VERSION 5.8 ;
BUSBITCHARS "[]" ;
DIVIDERCHAR "/" ;
UNITS
    DATABASE MICRONS 1000 ;
END UNITS

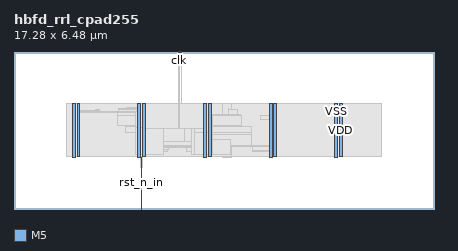
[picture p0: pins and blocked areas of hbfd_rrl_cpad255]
MACRO hbfd_rrl_cpad255
  FOREIGN hbfd_rrl_cpad255 0 0 ;
  CLASS BLOCK ;
  SIZE 17.28 BY 6.48 ;
  PIN clk
    DIRECTION INPUT ;
    USE SIGNAL ;
    PORT
      LAYER M5 ;
        RECT  6.768 6.396 6.792 6.48 ;
    END
  END clk
  PIN rst_n
    DIRECTION OUTPUT ;
    USE SIGNAL ;
    PORT
      LAYER M5 ;
        RECT  6.864 6.396 6.888 6.48 ;
    END
  END rst_n
  PIN rst_n_in
    DIRECTION INPUT ;
    USE SIGNAL ;
    PORT
      LAYER M5 ;
        RECT  5.232 0 5.256 0.084 ;
    END
    PORT
      LAYER M5 ;
        RECT  5.232 0.016 5.256 2.137 ;
    END
  END rst_n_in
  PIN VDD
    DIRECTION INOUT ;
    USE POWER ;
    PORT
      LAYER M5 ;
        RECT  13.392 2.151 13.512 4.329 ;
        RECT  10.692 2.151 10.812 4.329 ;
        RECT  7.992 2.151 8.112 4.329 ;
        RECT  5.292 2.151 5.412 4.329 ;
        RECT  2.592 2.151 2.712 4.329 ;
    END
  END VDD
  PIN VSS
    DIRECTION INOUT ;
    USE GROUND ;
    PORT
      LAYER M5 ;
        RECT  13.2 2.137 13.32 4.343 ;
        RECT  10.5 2.137 10.62 4.343 ;
        RECT  7.8 2.137 7.92 4.343 ;
        RECT  5.1 2.137 5.22 4.343 ;
        RECT  2.4 2.137 2.52 4.343 ;
    END
  END VSS
  # OT_OBS_CLOSED layer=M5 d_um=1.536 added=3
  OBS
    LAYER RVTN ;
     RECT  2.16 2.16 15.12 2.295 ;
     RECT  2.16 2.565 15.12 2.835 ;
     RECT  2.16 3.105 15.12 3.375 ;
     RECT  2.16 3.645 15.12 3.915 ;
     RECT  2.16 4.185 15.12 4.32 ;
    LAYER RVTP ;
     RECT  2.16 2.295 15.12 2.565 ;
     RECT  2.16 2.835 15.12 3.105 ;
     RECT  2.16 3.375 15.12 3.645 ;
     RECT  2.16 3.915 15.12 4.185 ;
    LAYER M1 ;
     RECT  2.16 2.151 15.12 4.329 ;
    LAYER M2 ;
     RECT  2.16 2.151 8.563 4.329 ;
     RECT  8.563 2.106 8.951 4.329 ;
     RECT  8.951 2.151 15.12 4.329 ;
    LAYER M3 ;
     RECT  5.256 1.723 5.274 2.143 ;
     RECT  8.568 2.101 8.946 2.143 ;
     RECT  7.815 2.143 8.946 2.251 ;
     RECT  6.12 2.251 6.138 2.371 ;
     RECT  7.308 2.251 8.946 2.371 ;
     RECT  10.515 2.143 10.605 2.371 ;
     RECT  2.415 2.143 2.505 2.413 ;
     RECT  5.115 2.143 5.274 2.413 ;
     RECT  9.828 2.371 10.605 2.413 ;
     RECT  13.215 2.143 13.305 2.413 ;
     RECT  5.115 2.413 5.397 2.461 ;
     RECT  6.12 2.371 6.318 2.461 ;
     RECT  5.115 2.461 6.354 2.533 ;
     RECT  7.092 2.371 8.946 2.533 ;
     RECT  5.115 2.533 8.946 2.569 ;
     RECT  9.828 2.413 10.797 2.569 ;
     RECT  5.115 2.569 10.797 2.633 ;
     RECT  5.115 2.633 9.774 3.067 ;
     RECT  5.004 3.067 9.774 3.145 ;
     RECT  4.608 3.145 9.774 3.407 ;
     RECT  4.608 3.407 9.342 3.415 ;
     RECT  10.515 2.633 10.797 3.685 ;
     RECT  4.248 3.415 9.342 3.839 ;
     RECT  10.152 3.685 10.797 3.839 ;
     RECT  7.815 3.839 9.306 3.869 ;
     RECT  7.815 3.869 9.234 3.875 ;
     RECT  2.415 2.413 2.697 3.979 ;
     RECT  2.415 3.979 3.366 3.991 ;
     RECT  4.248 3.839 6.894 4.013 ;
     RECT  2.415 3.991 3.51 4.067 ;
     RECT  7.815 3.875 8.097 4.067 ;
     RECT  10.515 3.839 10.797 4.067 ;
     RECT  13.215 2.413 13.497 4.067 ;
     RECT  3.348 4.067 3.51 4.109 ;
     RECT  4.284 4.013 6.894 4.109 ;
     RECT  8.82 3.875 9.198 4.109 ;
     RECT  4.284 4.109 5.526 4.145 ;
     RECT  8.82 4.109 8.838 4.145 ;
     RECT  4.644 4.145 5.526 4.181 ;
     RECT  5.115 4.181 5.526 4.289 ;
     RECT  2.415 4.067 2.505 4.337 ;
     RECT  5.115 4.289 5.205 4.337 ;
     RECT  7.815 4.067 7.905 4.337 ;
     RECT  10.515 4.067 10.605 4.337 ;
     RECT  13.215 4.067 13.305 4.337 ;
     RECT  6.876 4.109 6.894 6.365 ;
    LAYER M4 ;
     RECT  2.408 2.148 2.512 4.332 ;
     RECT  2.512 2.418 2.704 4.062 ;
     RECT  2.704 3.984 4.981 4.008 ;
     RECT  4.981 2.256 4.993 2.28 ;
     RECT  4.981 3.312 4.993 4.008 ;
     RECT  4.993 2.256 5.108 4.008 ;
     RECT  5.108 2.148 5.201 4.332 ;
     RECT  5.201 1.728 5.212 4.332 ;
     RECT  5.212 1.728 5.285 4.062 ;
     RECT  5.285 2.256 5.404 4.062 ;
     RECT  5.404 2.256 6.149 3.336 ;
     RECT  6.853 6.336 6.94 6.36 ;
     RECT  6.149 2.784 7.009 3.336 ;
     RECT  7.009 2.784 7.297 3.432 ;
     RECT  7.297 2.256 7.808 3.432 ;
     RECT  7.808 2.148 7.912 4.332 ;
     RECT  7.912 2.256 8.104 4.062 ;
     RECT  8.104 2.256 8.165 3.864 ;
     RECT  8.165 2.256 8.921 2.856 ;
     RECT  8.165 3.84 9.317 3.864 ;
     RECT  10.508 2.148 10.612 4.332 ;
     RECT  10.612 2.418 10.804 4.062 ;
     RECT  13.208 2.148 13.312 4.332 ;
     RECT  13.312 2.418 13.504 4.062 ;
    LAYER M5 ;
     RECT  2.4 2.137 2.52 2.151 ;
     RECT  5.1 2.137 5.256 2.151 ;
     RECT  7.8 2.137 7.92 2.151 ;
     RECT  10.5 2.137 10.62 2.151 ;
     RECT  13.2 2.137 13.32 2.151 ;
     RECT  5.1 2.151 5.412 2.245 ;
     RECT  7.8 2.151 8.112 2.245 ;
     RECT  7.44 2.245 8.112 3.155 ;
     RECT  4.992 2.245 5.412 3.347 ;
     RECT  2.4 2.151 2.712 4.329 ;
     RECT  5.1 3.347 5.412 4.329 ;
     RECT  7.8 3.155 8.112 4.329 ;
     RECT  10.5 2.151 10.812 4.329 ;
     RECT  13.2 2.151 13.512 4.329 ;
     RECT  2.4 4.329 2.52 4.343 ;
     RECT  5.1 4.329 5.22 4.343 ;
     RECT  7.8 4.329 7.92 4.343 ;
     RECT  10.5 4.329 10.62 4.343 ;
     RECT  13.2 4.329 13.32 4.343 ;
     RECT  6.768 3.301 6.792 6.325 ;
     RECT  6.768 6.325 6.888 6.396 ;
     RECT  6.792 6.396 6.864 6.416 ;
     RECT  7.44 3.155 7.8 3.301 ;
     RECT  5.412 3.301 6.768 4.329 ;
     RECT  6.792 3.301 7.8 4.343 ;
  END
END hbfd_rrl_cpad255
END LIBRARY
